VERSION 5.7 ;
  NOWIREEXTENSIONATPIN ON ;
  DIVIDERCHAR "/" ;
  BUSBITCHARS "[]" ;
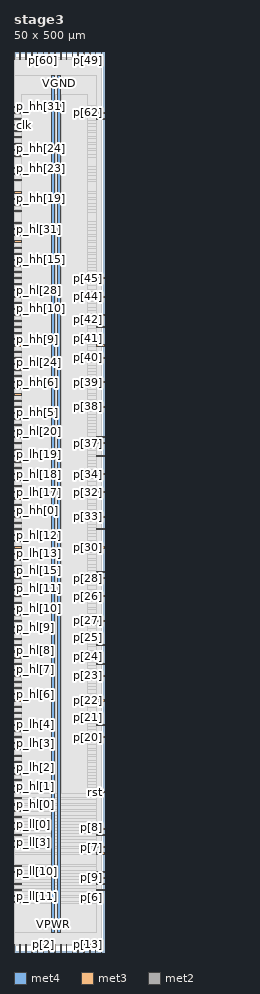
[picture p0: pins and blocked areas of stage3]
MACRO stage3
  CLASS BLOCK ;
  FOREIGN stage3 ;
  ORIGIN 0.000 0.000 ;
  SIZE 50.000 BY 500.000 ;
  PIN VGND
    DIRECTION INOUT ;
    USE GROUND ;
    PORT
      LAYER met4 ;
        RECT 24.340 10.640 25.940 487.120 ;
    END
  END VGND
  PIN VPWR
    DIRECTION INOUT ;
    USE POWER ;
    PORT
      LAYER met4 ;
        RECT 21.040 10.640 22.640 487.120 ;
    END
  END VPWR
  PIN clk
    DIRECTION INPUT ;
    USE SIGNAL ;
    ANTENNAGATEAREA 1.286700 ;
    ANTENNADIFFAREA 0.434700 ;
    PORT
      LAYER met3 ;
        RECT 0.000 459.040 4.000 459.640 ;
    END
  END clk
  PIN p[0]
    DIRECTION OUTPUT ;
    USE SIGNAL ;
    ANTENNADIFFAREA 0.445500 ;
    PORT
      LAYER met2 ;
        RECT 3.310 0.000 3.590 4.000 ;
    END
  END p[0]
  PIN p[10]
    DIRECTION OUTPUT ;
    USE SIGNAL ;
    ANTENNADIFFAREA 0.445500 ;
    PORT
      LAYER met2 ;
        RECT 0.090 0.000 0.370 4.000 ;
    END
  END p[10]
  PIN p[11]
    DIRECTION OUTPUT ;
    USE SIGNAL ;
    ANTENNADIFFAREA 0.445500 ;
    PORT
      LAYER met2 ;
        RECT 29.070 0.000 29.350 4.000 ;
    END
  END p[11]
  PIN p[12]
    DIRECTION OUTPUT ;
    USE SIGNAL ;
    ANTENNADIFFAREA 0.445500 ;
    PORT
      LAYER met2 ;
        RECT 9.750 0.000 10.030 4.000 ;
    END
  END p[12]
  PIN p[13]
    DIRECTION OUTPUT ;
    USE SIGNAL ;
    ANTENNADIFFAREA 0.445500 ;
    PORT
      LAYER met2 ;
        RECT 41.950 0.000 42.230 4.000 ;
    END
  END p[13]
  PIN p[14]
    DIRECTION OUTPUT ;
    USE SIGNAL ;
    ANTENNADIFFAREA 0.445500 ;
    PORT
      LAYER met2 ;
        RECT 12.970 0.000 13.250 4.000 ;
    END
  END p[14]
  PIN p[15]
    DIRECTION OUTPUT ;
    USE SIGNAL ;
    ANTENNADIFFAREA 0.445500 ;
    PORT
      LAYER met2 ;
        RECT 22.630 0.000 22.910 4.000 ;
    END
  END p[15]
  PIN p[16]
    DIRECTION OUTPUT ;
    USE SIGNAL ;
    ANTENNADIFFAREA 0.445500 ;
    PORT
      LAYER met2 ;
        RECT 32.290 0.000 32.570 4.000 ;
    END
  END p[16]
  PIN p[17]
    DIRECTION OUTPUT ;
    USE SIGNAL ;
    ANTENNADIFFAREA 0.445500 ;
    PORT
      LAYER met2 ;
        RECT 38.730 0.000 39.010 4.000 ;
    END
  END p[17]
  PIN p[18]
    DIRECTION OUTPUT ;
    USE SIGNAL ;
    ANTENNADIFFAREA 0.445500 ;
    PORT
      LAYER met2 ;
        RECT 6.530 0.000 6.810 4.000 ;
    END
  END p[18]
  PIN p[19]
    DIRECTION OUTPUT ;
    USE SIGNAL ;
    ANTENNADIFFAREA 0.445500 ;
    PORT
      LAYER met2 ;
        RECT 25.850 0.000 26.130 4.000 ;
    END
  END p[19]
  PIN p[1]
    DIRECTION OUTPUT ;
    USE SIGNAL ;
    ANTENNADIFFAREA 0.445500 ;
    PORT
      LAYER met2 ;
        RECT 35.510 0.000 35.790 4.000 ;
    END
  END p[1]
  PIN p[20]
    DIRECTION OUTPUT ;
    USE SIGNAL ;
    ANTENNADIFFAREA 0.445500 ;
    PORT
      LAYER met3 ;
        RECT 46.000 119.040 50.000 119.640 ;
    END
  END p[20]
  PIN p[21]
    DIRECTION OUTPUT ;
    USE SIGNAL ;
    ANTENNADIFFAREA 0.445500 ;
    PORT
      LAYER met3 ;
        RECT 46.000 125.840 50.000 126.440 ;
    END
  END p[21]
  PIN p[22]
    DIRECTION OUTPUT ;
    USE SIGNAL ;
    ANTENNADIFFAREA 0.445500 ;
    PORT
      LAYER met3 ;
        RECT 46.000 139.440 50.000 140.040 ;
    END
  END p[22]
  PIN p[23]
    DIRECTION OUTPUT ;
    USE SIGNAL ;
    ANTENNADIFFAREA 0.445500 ;
    PORT
      LAYER met3 ;
        RECT 46.000 153.040 50.000 153.640 ;
    END
  END p[23]
  PIN p[24]
    DIRECTION OUTPUT ;
    USE SIGNAL ;
    ANTENNADIFFAREA 0.445500 ;
    PORT
      LAYER met3 ;
        RECT 46.000 159.840 50.000 160.440 ;
    END
  END p[24]
  PIN p[25]
    DIRECTION OUTPUT ;
    USE SIGNAL ;
    ANTENNADIFFAREA 0.445500 ;
    PORT
      LAYER met3 ;
        RECT 46.000 170.040 50.000 170.640 ;
    END
  END p[25]
  PIN p[26]
    DIRECTION OUTPUT ;
    USE SIGNAL ;
    ANTENNADIFFAREA 0.445500 ;
    PORT
      LAYER met3 ;
        RECT 46.000 197.240 50.000 197.840 ;
    END
  END p[26]
  PIN p[27]
    DIRECTION OUTPUT ;
    USE SIGNAL ;
    ANTENNADIFFAREA 0.445500 ;
    PORT
      LAYER met3 ;
        RECT 46.000 183.640 50.000 184.240 ;
    END
  END p[27]
  PIN p[28]
    DIRECTION OUTPUT ;
    USE SIGNAL ;
    ANTENNADIFFAREA 0.445500 ;
    PORT
      LAYER met3 ;
        RECT 46.000 207.440 50.000 208.040 ;
    END
  END p[28]
  PIN p[29]
    DIRECTION OUTPUT ;
    USE SIGNAL ;
    ANTENNADIFFAREA 0.445500 ;
    PORT
      LAYER met3 ;
        RECT 46.000 210.840 50.000 211.440 ;
    END
  END p[29]
  PIN p[2]
    DIRECTION OUTPUT ;
    USE SIGNAL ;
    ANTENNADIFFAREA 0.445500 ;
    PORT
      LAYER met2 ;
        RECT 16.190 0.000 16.470 4.000 ;
    END
  END p[2]
  PIN p[30]
    DIRECTION OUTPUT ;
    USE SIGNAL ;
    ANTENNADIFFAREA 0.445500 ;
    PORT
      LAYER met3 ;
        RECT 46.000 224.440 50.000 225.040 ;
    END
  END p[30]
  PIN p[31]
    DIRECTION OUTPUT ;
    USE SIGNAL ;
    ANTENNADIFFAREA 0.445500 ;
    PORT
      LAYER met3 ;
        RECT 46.000 234.640 50.000 235.240 ;
    END
  END p[31]
  PIN p[32]
    DIRECTION OUTPUT ;
    USE SIGNAL ;
    ANTENNADIFFAREA 0.445500 ;
    PORT
      LAYER met3 ;
        RECT 46.000 255.040 50.000 255.640 ;
    END
  END p[32]
  PIN p[33]
    DIRECTION OUTPUT ;
    USE SIGNAL ;
    ANTENNADIFFAREA 0.445500 ;
    PORT
      LAYER met3 ;
        RECT 46.000 241.440 50.000 242.040 ;
    END
  END p[33]
  PIN p[34]
    DIRECTION OUTPUT ;
    USE SIGNAL ;
    ANTENNADIFFAREA 0.445500 ;
    PORT
      LAYER met3 ;
        RECT 46.000 265.240 50.000 265.840 ;
    END
  END p[34]
  PIN p[35]
    DIRECTION OUTPUT ;
    USE SIGNAL ;
    ANTENNADIFFAREA 0.445500 ;
    PORT
      LAYER met3 ;
        RECT 46.000 275.440 50.000 276.040 ;
    END
  END p[35]
  PIN p[36]
    DIRECTION OUTPUT ;
    USE SIGNAL ;
    ANTENNADIFFAREA 0.445500 ;
    PORT
      LAYER met3 ;
        RECT 46.000 285.640 50.000 286.240 ;
    END
  END p[36]
  PIN p[37]
    DIRECTION OUTPUT ;
    USE SIGNAL ;
    ANTENNADIFFAREA 0.445500 ;
    PORT
      LAYER met3 ;
        RECT 46.000 282.240 50.000 282.840 ;
    END
  END p[37]
  PIN p[38]
    DIRECTION OUTPUT ;
    USE SIGNAL ;
    ANTENNADIFFAREA 0.445500 ;
    PORT
      LAYER met3 ;
        RECT 46.000 302.640 50.000 303.240 ;
    END
  END p[38]
  PIN p[39]
    DIRECTION OUTPUT ;
    USE SIGNAL ;
    ANTENNADIFFAREA 0.445500 ;
    PORT
      LAYER met3 ;
        RECT 46.000 316.240 50.000 316.840 ;
    END
  END p[39]
  PIN p[3]
    DIRECTION OUTPUT ;
    USE SIGNAL ;
    ANTENNADIFFAREA 0.445500 ;
    PORT
      LAYER met2 ;
        RECT 19.410 0.000 19.690 4.000 ;
    END
  END p[3]
  PIN p[40]
    DIRECTION OUTPUT ;
    USE SIGNAL ;
    ANTENNADIFFAREA 0.445500 ;
    PORT
      LAYER met3 ;
        RECT 46.000 329.840 50.000 330.440 ;
    END
  END p[40]
  PIN p[41]
    DIRECTION OUTPUT ;
    USE SIGNAL ;
    ANTENNADIFFAREA 0.445500 ;
    PORT
      LAYER met3 ;
        RECT 46.000 336.640 50.000 337.240 ;
    END
  END p[41]
  PIN p[42]
    DIRECTION OUTPUT ;
    USE SIGNAL ;
    ANTENNADIFFAREA 0.445500 ;
    PORT
      LAYER met3 ;
        RECT 46.000 346.840 50.000 347.440 ;
    END
  END p[42]
  PIN p[43]
    DIRECTION OUTPUT ;
    USE SIGNAL ;
    ANTENNADIFFAREA 0.445500 ;
    PORT
      LAYER met3 ;
        RECT 46.000 353.640 50.000 354.240 ;
    END
  END p[43]
  PIN p[44]
    DIRECTION OUTPUT ;
    USE SIGNAL ;
    ANTENNADIFFAREA 0.445500 ;
    PORT
      LAYER met3 ;
        RECT 46.000 363.840 50.000 364.440 ;
    END
  END p[44]
  PIN p[45]
    DIRECTION OUTPUT ;
    USE SIGNAL ;
    ANTENNADIFFAREA 0.445500 ;
    PORT
      LAYER met3 ;
        RECT 46.000 374.040 50.000 374.640 ;
    END
  END p[45]
  PIN p[46]
    DIRECTION OUTPUT ;
    USE SIGNAL ;
    ANTENNADIFFAREA 0.445500 ;
    PORT
      LAYER met2 ;
        RECT 38.730 496.000 39.010 500.000 ;
    END
  END p[46]
  PIN p[47]
    DIRECTION OUTPUT ;
    USE SIGNAL ;
    ANTENNADIFFAREA 0.445500 ;
    PORT
      LAYER met2 ;
        RECT 3.310 496.000 3.590 500.000 ;
    END
  END p[47]
  PIN p[48]
    DIRECTION OUTPUT ;
    USE SIGNAL ;
    ANTENNADIFFAREA 0.445500 ;
    PORT
      LAYER met2 ;
        RECT 0.090 496.000 0.370 500.000 ;
    END
  END p[48]
  PIN p[49]
    DIRECTION OUTPUT ;
    USE SIGNAL ;
    ANTENNADIFFAREA 0.445500 ;
    PORT
      LAYER met2 ;
        RECT 41.950 496.000 42.230 500.000 ;
    END
  END p[49]
  PIN p[4]
    DIRECTION OUTPUT ;
    USE SIGNAL ;
    ANTENNADIFFAREA 0.445500 ;
    PORT
      LAYER met2 ;
        RECT 45.170 0.000 45.450 4.000 ;
    END
  END p[4]
  PIN p[50]
    DIRECTION OUTPUT ;
    USE SIGNAL ;
    ANTENNADIFFAREA 0.445500 ;
    PORT
      LAYER met2 ;
        RECT 6.530 496.000 6.810 500.000 ;
    END
  END p[50]
  PIN p[51]
    DIRECTION OUTPUT ;
    USE SIGNAL ;
    ANTENNADIFFAREA 0.445500 ;
    PORT
      LAYER met2 ;
        RECT 35.510 496.000 35.790 500.000 ;
    END
  END p[51]
  PIN p[52]
    DIRECTION OUTPUT ;
    USE SIGNAL ;
    ANTENNADIFFAREA 0.445500 ;
    PORT
      LAYER met2 ;
        RECT 12.970 496.000 13.250 500.000 ;
    END
  END p[52]
  PIN p[53]
    DIRECTION OUTPUT ;
    USE SIGNAL ;
    ANTENNADIFFAREA 0.445500 ;
    PORT
      LAYER met2 ;
        RECT 9.750 496.000 10.030 500.000 ;
    END
  END p[53]
  PIN p[54]
    DIRECTION OUTPUT ;
    USE SIGNAL ;
    ANTENNADIFFAREA 0.445500 ;
    PORT
      LAYER met2 ;
        RECT 25.850 496.000 26.130 500.000 ;
    END
  END p[54]
  PIN p[55]
    DIRECTION OUTPUT ;
    USE SIGNAL ;
    ANTENNADIFFAREA 0.445500 ;
    PORT
      LAYER met2 ;
        RECT 22.630 496.000 22.910 500.000 ;
    END
  END p[55]
  PIN p[56]
    DIRECTION OUTPUT ;
    USE SIGNAL ;
    ANTENNADIFFAREA 0.445500 ;
    PORT
      LAYER met2 ;
        RECT 48.390 496.000 48.670 500.000 ;
    END
  END p[56]
  PIN p[57]
    DIRECTION OUTPUT ;
    USE SIGNAL ;
    ANTENNADIFFAREA 0.445500 ;
    PORT
      LAYER met2 ;
        RECT 29.070 496.000 29.350 500.000 ;
    END
  END p[57]
  PIN p[58]
    DIRECTION OUTPUT ;
    USE SIGNAL ;
    ANTENNADIFFAREA 0.445500 ;
    PORT
      LAYER met2 ;
        RECT 45.170 496.000 45.450 500.000 ;
    END
  END p[58]
  PIN p[59]
    DIRECTION OUTPUT ;
    USE SIGNAL ;
    ANTENNADIFFAREA 0.445500 ;
    PORT
      LAYER met2 ;
        RECT 19.410 496.000 19.690 500.000 ;
    END
  END p[59]
  PIN p[5]
    DIRECTION OUTPUT ;
    USE SIGNAL ;
    ANTENNADIFFAREA 0.445500 ;
    PORT
      LAYER met2 ;
        RECT 48.390 0.000 48.670 4.000 ;
    END
  END p[5]
  PIN p[60]
    DIRECTION OUTPUT ;
    USE SIGNAL ;
    ANTENNADIFFAREA 0.445500 ;
    PORT
      LAYER met2 ;
        RECT 16.190 496.000 16.470 500.000 ;
    END
  END p[60]
  PIN p[61]
    DIRECTION OUTPUT ;
    USE SIGNAL ;
    ANTENNADIFFAREA 0.445500 ;
    PORT
      LAYER met2 ;
        RECT 32.290 496.000 32.570 500.000 ;
    END
  END p[61]
  PIN p[62]
    DIRECTION OUTPUT ;
    USE SIGNAL ;
    ANTENNADIFFAREA 0.445500 ;
    PORT
      LAYER met3 ;
        RECT 46.000 465.840 50.000 466.440 ;
    END
  END p[62]
  PIN p[63]
    DIRECTION OUTPUT ;
    USE SIGNAL ;
    ANTENNADIFFAREA 0.445500 ;
    PORT
      LAYER met3 ;
        RECT 46.000 462.440 50.000 463.040 ;
    END
  END p[63]
  PIN p[6]
    DIRECTION OUTPUT ;
    USE SIGNAL ;
    ANTENNADIFFAREA 0.445500 ;
    PORT
      LAYER met3 ;
        RECT 46.000 34.040 50.000 34.640 ;
    END
  END p[6]
  PIN p[7]
    DIRECTION OUTPUT ;
    USE SIGNAL ;
    ANTENNADIFFAREA 0.445500 ;
    PORT
      LAYER met3 ;
        RECT 46.000 57.840 50.000 58.440 ;
    END
  END p[7]
  PIN p[8]
    DIRECTION OUTPUT ;
    USE SIGNAL ;
    ANTENNADIFFAREA 0.445500 ;
    PORT
      LAYER met3 ;
        RECT 46.000 64.640 50.000 65.240 ;
    END
  END p[8]
  PIN p[9]
    DIRECTION OUTPUT ;
    USE SIGNAL ;
    ANTENNADIFFAREA 0.445500 ;
    PORT
      LAYER met3 ;
        RECT 46.000 40.840 50.000 41.440 ;
    END
  END p[9]
  PIN p_hh[0]
    DIRECTION INPUT ;
    USE SIGNAL ;
    ANTENNAGATEAREA 0.631200 ;
    ANTENNADIFFAREA 0.434700 ;
    PORT
      LAYER met3 ;
        RECT 0.000 244.840 4.000 245.440 ;
    END
  END p_hh[0]
  PIN p_hh[10]
    DIRECTION INPUT ;
    USE SIGNAL ;
    ANTENNAGATEAREA 0.631200 ;
    ANTENNADIFFAREA 0.434700 ;
    PORT
      LAYER met3 ;
        RECT 0.000 357.040 4.000 357.640 ;
    END
  END p_hh[10]
  PIN p_hh[11]
    DIRECTION INPUT ;
    USE SIGNAL ;
    ANTENNAGATEAREA 0.631200 ;
    ANTENNADIFFAREA 0.434700 ;
    PORT
      LAYER met3 ;
        RECT 0.000 360.440 4.000 361.040 ;
    END
  END p_hh[11]
  PIN p_hh[12]
    DIRECTION INPUT ;
    USE SIGNAL ;
    ANTENNAGATEAREA 0.631200 ;
    ANTENNADIFFAREA 0.434700 ;
    PORT
      LAYER met3 ;
        RECT 0.000 380.840 4.000 381.440 ;
    END
  END p_hh[12]
  PIN p_hh[13]
    DIRECTION INPUT ;
    USE SIGNAL ;
    ANTENNAGATEAREA 0.631200 ;
    ANTENNADIFFAREA 0.434700 ;
    PORT
      LAYER met3 ;
        RECT 0.000 363.840 4.000 364.440 ;
    END
  END p_hh[13]
  PIN p_hh[14]
    DIRECTION INPUT ;
    USE SIGNAL ;
    ANTENNAGATEAREA 0.631200 ;
    ANTENNADIFFAREA 0.434700 ;
    PORT
      LAYER met3 ;
        RECT 0.000 394.440 4.000 395.040 ;
    END
  END p_hh[14]
  PIN p_hh[15]
    DIRECTION INPUT ;
    USE SIGNAL ;
    ANTENNAGATEAREA 0.631200 ;
    ANTENNADIFFAREA 0.434700 ;
    PORT
      LAYER met3 ;
        RECT 0.000 384.240 4.000 384.840 ;
    END
  END p_hh[15]
  PIN p_hh[16]
    DIRECTION INPUT ;
    USE SIGNAL ;
    ANTENNAGATEAREA 0.631200 ;
    ANTENNADIFFAREA 0.434700 ;
    PORT
      LAYER met3 ;
        RECT 0.000 404.640 4.000 405.240 ;
    END
  END p_hh[16]
  PIN p_hh[17]
    DIRECTION INPUT ;
    USE SIGNAL ;
    ANTENNAGATEAREA 0.631200 ;
    ANTENNADIFFAREA 0.434700 ;
    PORT
      LAYER met3 ;
        RECT 0.000 411.440 4.000 412.040 ;
    END
  END p_hh[17]
  PIN p_hh[18]
    DIRECTION INPUT ;
    USE SIGNAL ;
    ANTENNAGATEAREA 0.631200 ;
    ANTENNADIFFAREA 0.434700 ;
    PORT
      LAYER met3 ;
        RECT 0.000 414.840 4.000 415.440 ;
    END
  END p_hh[18]
  PIN p_hh[19]
    DIRECTION INPUT ;
    USE SIGNAL ;
    ANTENNAGATEAREA 0.631200 ;
    ANTENNADIFFAREA 0.434700 ;
    PORT
      LAYER met3 ;
        RECT 0.000 418.240 4.000 418.840 ;
    END
  END p_hh[19]
  PIN p_hh[1]
    DIRECTION INPUT ;
    USE SIGNAL ;
    ANTENNAGATEAREA 0.631200 ;
    ANTENNADIFFAREA 0.434700 ;
    PORT
      LAYER met3 ;
        RECT 0.000 241.440 4.000 242.040 ;
    END
  END p_hh[1]
  PIN p_hh[20]
    DIRECTION INPUT ;
    USE SIGNAL ;
    ANTENNAGATEAREA 0.631200 ;
    ANTENNADIFFAREA 0.434700 ;
    PORT
      LAYER met3 ;
        RECT 0.000 431.840 4.000 432.440 ;
    END
  END p_hh[20]
  PIN p_hh[21]
    DIRECTION INPUT ;
    USE SIGNAL ;
    ANTENNAGATEAREA 0.631200 ;
    ANTENNADIFFAREA 0.434700 ;
    PORT
      LAYER met3 ;
        RECT 0.000 428.440 4.000 429.040 ;
    END
  END p_hh[21]
  PIN p_hh[22]
    DIRECTION INPUT ;
    USE SIGNAL ;
    ANTENNAGATEAREA 0.631200 ;
    ANTENNADIFFAREA 0.434700 ;
    PORT
      LAYER met3 ;
        RECT 0.000 421.640 4.000 422.240 ;
    END
  END p_hh[22]
  PIN p_hh[23]
    DIRECTION INPUT ;
    USE SIGNAL ;
    ANTENNAGATEAREA 0.631200 ;
    ANTENNADIFFAREA 0.434700 ;
    PORT
      LAYER met3 ;
        RECT 0.000 435.240 4.000 435.840 ;
    END
  END p_hh[23]
  PIN p_hh[24]
    DIRECTION INPUT ;
    USE SIGNAL ;
    ANTENNAGATEAREA 0.631200 ;
    ANTENNADIFFAREA 0.434700 ;
    PORT
      LAYER met3 ;
        RECT 0.000 442.040 4.000 442.640 ;
    END
  END p_hh[24]
  PIN p_hh[25]
    DIRECTION INPUT ;
    USE SIGNAL ;
    ANTENNAGATEAREA 0.631200 ;
    ANTENNADIFFAREA 0.434700 ;
    PORT
      LAYER met3 ;
        RECT 0.000 445.440 4.000 446.040 ;
    END
  END p_hh[25]
  PIN p_hh[26]
    DIRECTION INPUT ;
    USE SIGNAL ;
    ANTENNAGATEAREA 0.631200 ;
    ANTENNADIFFAREA 0.434700 ;
    PORT
      LAYER met3 ;
        RECT 0.000 448.840 4.000 449.440 ;
    END
  END p_hh[26]
  PIN p_hh[27]
    DIRECTION INPUT ;
    USE SIGNAL ;
    ANTENNAGATEAREA 0.631200 ;
    ANTENNADIFFAREA 0.434700 ;
    PORT
      LAYER met3 ;
        RECT 0.000 452.240 4.000 452.840 ;
    END
  END p_hh[27]
  PIN p_hh[28]
    DIRECTION INPUT ;
    USE SIGNAL ;
    ANTENNAGATEAREA 0.631200 ;
    ANTENNADIFFAREA 0.434700 ;
    PORT
      LAYER met3 ;
        RECT 0.000 455.640 4.000 456.240 ;
    END
  END p_hh[28]
  PIN p_hh[29]
    DIRECTION INPUT ;
    USE SIGNAL ;
    ANTENNAGATEAREA 0.631200 ;
    ANTENNADIFFAREA 0.434700 ;
    PORT
      LAYER met3 ;
        RECT 0.000 462.440 4.000 463.040 ;
    END
  END p_hh[29]
  PIN p_hh[2]
    DIRECTION INPUT ;
    USE SIGNAL ;
    ANTENNAGATEAREA 0.631200 ;
    ANTENNADIFFAREA 0.434700 ;
    PORT
      LAYER met3 ;
        RECT 0.000 261.840 4.000 262.440 ;
    END
  END p_hh[2]
  PIN p_hh[30]
    DIRECTION INPUT ;
    USE SIGNAL ;
    ANTENNAGATEAREA 0.631200 ;
    ANTENNADIFFAREA 0.434700 ;
    PORT
      LAYER met3 ;
        RECT 0.000 465.840 4.000 466.440 ;
    END
  END p_hh[30]
  PIN p_hh[31]
    DIRECTION INPUT ;
    USE SIGNAL ;
    ANTENNAGATEAREA 0.631200 ;
    ANTENNADIFFAREA 0.434700 ;
    PORT
      LAYER met3 ;
        RECT 0.000 469.240 4.000 469.840 ;
    END
  END p_hh[31]
  PIN p_hh[3]
    DIRECTION INPUT ;
    USE SIGNAL ;
    ANTENNAGATEAREA 0.631200 ;
    ANTENNADIFFAREA 0.434700 ;
    PORT
      LAYER met3 ;
        RECT 0.000 278.840 4.000 279.440 ;
    END
  END p_hh[3]
  PIN p_hh[4]
    DIRECTION INPUT ;
    USE SIGNAL ;
    ANTENNAGATEAREA 0.631200 ;
    ANTENNADIFFAREA 0.434700 ;
    PORT
      LAYER met3 ;
        RECT 0.000 285.640 4.000 286.240 ;
    END
  END p_hh[4]
  PIN p_hh[5]
    DIRECTION INPUT ;
    USE SIGNAL ;
    ANTENNAGATEAREA 0.631200 ;
    ANTENNADIFFAREA 0.434700 ;
    PORT
      LAYER met3 ;
        RECT 0.000 299.240 4.000 299.840 ;
    END
  END p_hh[5]
  PIN p_hh[6]
    DIRECTION INPUT ;
    USE SIGNAL ;
    ANTENNAGATEAREA 0.631200 ;
    ANTENNADIFFAREA 0.434700 ;
    PORT
      LAYER met3 ;
        RECT 0.000 316.240 4.000 316.840 ;
    END
  END p_hh[6]
  PIN p_hh[7]
    DIRECTION INPUT ;
    USE SIGNAL ;
    ANTENNAGATEAREA 0.631200 ;
    ANTENNADIFFAREA 0.434700 ;
    PORT
      LAYER met3 ;
        RECT 0.000 319.640 4.000 320.240 ;
    END
  END p_hh[7]
  PIN p_hh[8]
    DIRECTION INPUT ;
    USE SIGNAL ;
    ANTENNAGATEAREA 0.631200 ;
    ANTENNADIFFAREA 0.434700 ;
    PORT
      LAYER met3 ;
        RECT 0.000 329.840 4.000 330.440 ;
    END
  END p_hh[8]
  PIN p_hh[9]
    DIRECTION INPUT ;
    USE SIGNAL ;
    ANTENNAGATEAREA 0.631200 ;
    ANTENNADIFFAREA 0.434700 ;
    PORT
      LAYER met3 ;
        RECT 0.000 340.040 4.000 340.640 ;
    END
  END p_hh[9]
  PIN p_hl[0]
    DIRECTION INPUT ;
    USE SIGNAL ;
    ANTENNAGATEAREA 0.647700 ;
    ANTENNADIFFAREA 0.434700 ;
    PORT
      LAYER met3 ;
        RECT 0.000 81.640 4.000 82.240 ;
    END
  END p_hl[0]
  PIN p_hl[10]
    DIRECTION INPUT ;
    USE SIGNAL ;
    ANTENNAGATEAREA 0.631200 ;
    ANTENNADIFFAREA 0.434700 ;
    PORT
      LAYER met3 ;
        RECT 0.000 190.440 4.000 191.040 ;
    END
  END p_hl[10]
  PIN p_hl[11]
    DIRECTION INPUT ;
    USE SIGNAL ;
    ANTENNAGATEAREA 0.631200 ;
    ANTENNADIFFAREA 0.434700 ;
    PORT
      LAYER met3 ;
        RECT 0.000 197.240 4.000 197.840 ;
    END
  END p_hl[11]
  PIN p_hl[12]
    DIRECTION INPUT ;
    USE SIGNAL ;
    ANTENNAGATEAREA 0.631200 ;
    ANTENNADIFFAREA 0.434700 ;
    PORT
      LAYER met3 ;
        RECT 0.000 231.240 4.000 231.840 ;
    END
  END p_hl[12]
  PIN p_hl[13]
    DIRECTION INPUT ;
    USE SIGNAL ;
    ANTENNAGATEAREA 0.631200 ;
    ANTENNADIFFAREA 0.434700 ;
    PORT
      LAYER met3 ;
        RECT 0.000 217.640 4.000 218.240 ;
    END
  END p_hl[13]
  PIN p_hl[14]
    DIRECTION INPUT ;
    USE SIGNAL ;
    ANTENNAGATEAREA 0.631200 ;
    ANTENNADIFFAREA 0.434700 ;
    PORT
      LAYER met3 ;
        RECT 0.000 227.840 4.000 228.440 ;
    END
  END p_hl[14]
  PIN p_hl[15]
    DIRECTION INPUT ;
    USE SIGNAL ;
    ANTENNAGATEAREA 0.631200 ;
    ANTENNADIFFAREA 0.434700 ;
    PORT
      LAYER met3 ;
        RECT 0.000 207.440 4.000 208.040 ;
    END
  END p_hl[15]
  PIN p_hl[16]
    DIRECTION INPUT ;
    USE SIGNAL ;
    ANTENNAGATEAREA 0.631200 ;
    ANTENNADIFFAREA 0.434700 ;
    PORT
      LAYER met3 ;
        RECT 0.000 258.440 4.000 259.040 ;
    END
  END p_hl[16]
  PIN p_hl[17]
    DIRECTION INPUT ;
    USE SIGNAL ;
    ANTENNAGATEAREA 0.631200 ;
    ANTENNADIFFAREA 0.434700 ;
    PORT
      LAYER met3 ;
        RECT 0.000 251.640 4.000 252.240 ;
    END
  END p_hl[17]
  PIN p_hl[18]
    DIRECTION INPUT ;
    USE SIGNAL ;
    ANTENNAGATEAREA 0.631200 ;
    ANTENNADIFFAREA 0.434700 ;
    PORT
      LAYER met3 ;
        RECT 0.000 265.240 4.000 265.840 ;
    END
  END p_hl[18]
  PIN p_hl[19]
    DIRECTION INPUT ;
    USE SIGNAL ;
    ANTENNAGATEAREA 0.631200 ;
    ANTENNADIFFAREA 0.434700 ;
    PORT
      LAYER met3 ;
        RECT 0.000 268.640 4.000 269.240 ;
    END
  END p_hl[19]
  PIN p_hl[1]
    DIRECTION INPUT ;
    USE SIGNAL ;
    ANTENNAGATEAREA 0.647700 ;
    ANTENNADIFFAREA 0.434700 ;
    PORT
      LAYER met3 ;
        RECT 0.000 91.840 4.000 92.440 ;
    END
  END p_hl[1]
  PIN p_hl[20]
    DIRECTION INPUT ;
    USE SIGNAL ;
    ANTENNAGATEAREA 0.631200 ;
    ANTENNADIFFAREA 0.434700 ;
    PORT
      LAYER met3 ;
        RECT 0.000 289.040 4.000 289.640 ;
    END
  END p_hl[20]
  PIN p_hl[21]
    DIRECTION INPUT ;
    USE SIGNAL ;
    ANTENNAGATEAREA 0.631200 ;
    ANTENNADIFFAREA 0.434700 ;
    PORT
      LAYER met3 ;
        RECT 0.000 295.840 4.000 296.440 ;
    END
  END p_hl[21]
  PIN p_hl[22]
    DIRECTION INPUT ;
    USE SIGNAL ;
    ANTENNAGATEAREA 0.631200 ;
    ANTENNADIFFAREA 0.434700 ;
    PORT
      LAYER met3 ;
        RECT 0.000 312.840 4.000 313.440 ;
    END
  END p_hl[22]
  PIN p_hl[23]
    DIRECTION INPUT ;
    USE SIGNAL ;
    ANTENNAGATEAREA 0.631200 ;
    ANTENNADIFFAREA 0.434700 ;
    PORT
      LAYER met3 ;
        RECT 0.000 306.040 4.000 306.640 ;
    END
  END p_hl[23]
  PIN p_hl[24]
    DIRECTION INPUT ;
    USE SIGNAL ;
    ANTENNAGATEAREA 0.647700 ;
    ANTENNADIFFAREA 0.434700 ;
    PORT
      LAYER met3 ;
        RECT 0.000 323.040 4.000 323.640 ;
    END
  END p_hl[24]
  PIN p_hl[25]
    DIRECTION INPUT ;
    USE SIGNAL ;
    ANTENNAGATEAREA 0.631200 ;
    ANTENNADIFFAREA 0.434700 ;
    PORT
      LAYER met3 ;
        RECT 0.000 336.640 4.000 337.240 ;
    END
  END p_hl[25]
  PIN p_hl[26]
    DIRECTION INPUT ;
    USE SIGNAL ;
    ANTENNAGATEAREA 0.631200 ;
    ANTENNADIFFAREA 0.434700 ;
    PORT
      LAYER met3 ;
        RECT 0.000 343.440 4.000 344.040 ;
    END
  END p_hl[26]
  PIN p_hl[27]
    DIRECTION INPUT ;
    USE SIGNAL ;
    ANTENNAGATEAREA 0.631200 ;
    ANTENNADIFFAREA 0.434700 ;
    PORT
      LAYER met3 ;
        RECT 0.000 353.640 4.000 354.240 ;
    END
  END p_hl[27]
  PIN p_hl[28]
    DIRECTION INPUT ;
    USE SIGNAL ;
    ANTENNAGATEAREA 0.631200 ;
    ANTENNADIFFAREA 0.434700 ;
    PORT
      LAYER met3 ;
        RECT 0.000 367.240 4.000 367.840 ;
    END
  END p_hl[28]
  PIN p_hl[29]
    DIRECTION INPUT ;
    USE SIGNAL ;
    ANTENNAGATEAREA 0.631200 ;
    ANTENNADIFFAREA 0.434700 ;
    PORT
      LAYER met3 ;
        RECT 0.000 377.440 4.000 378.040 ;
    END
  END p_hl[29]
  PIN p_hl[2]
    DIRECTION INPUT ;
    USE SIGNAL ;
    ANTENNAGATEAREA 0.631200 ;
    ANTENNADIFFAREA 0.434700 ;
    PORT
      LAYER met3 ;
        RECT 0.000 105.440 4.000 106.040 ;
    END
  END p_hl[2]
  PIN p_hl[30]
    DIRECTION INPUT ;
    USE SIGNAL ;
    ANTENNAGATEAREA 0.631200 ;
    ANTENNADIFFAREA 0.434700 ;
    PORT
      LAYER met3 ;
        RECT 0.000 387.640 4.000 388.240 ;
    END
  END p_hl[30]
  PIN p_hl[31]
    DIRECTION INPUT ;
    USE SIGNAL ;
    ANTENNAGATEAREA 0.631200 ;
    ANTENNADIFFAREA 0.434700 ;
    PORT
      LAYER met3 ;
        RECT 0.000 401.240 4.000 401.840 ;
    END
  END p_hl[31]
  PIN p_hl[3]
    DIRECTION INPUT ;
    USE SIGNAL ;
    ANTENNAGATEAREA 0.631200 ;
    ANTENNADIFFAREA 0.434700 ;
    PORT
      LAYER met3 ;
        RECT 0.000 112.240 4.000 112.840 ;
    END
  END p_hl[3]
  PIN p_hl[4]
    DIRECTION INPUT ;
    USE SIGNAL ;
    ANTENNAGATEAREA 0.631200 ;
    ANTENNADIFFAREA 0.434700 ;
    PORT
      LAYER met3 ;
        RECT 0.000 122.440 4.000 123.040 ;
    END
  END p_hl[4]
  PIN p_hl[5]
    DIRECTION INPUT ;
    USE SIGNAL ;
    ANTENNAGATEAREA 0.631200 ;
    ANTENNADIFFAREA 0.434700 ;
    PORT
      LAYER met3 ;
        RECT 0.000 132.640 4.000 133.240 ;
    END
  END p_hl[5]
  PIN p_hl[6]
    DIRECTION INPUT ;
    USE SIGNAL ;
    ANTENNAGATEAREA 0.647700 ;
    ANTENNADIFFAREA 0.434700 ;
    PORT
      LAYER met3 ;
        RECT 0.000 142.840 4.000 143.440 ;
    END
  END p_hl[6]
  PIN p_hl[7]
    DIRECTION INPUT ;
    USE SIGNAL ;
    ANTENNAGATEAREA 0.631200 ;
    ANTENNADIFFAREA 0.434700 ;
    PORT
      LAYER met3 ;
        RECT 0.000 156.440 4.000 157.040 ;
    END
  END p_hl[7]
  PIN p_hl[8]
    DIRECTION INPUT ;
    USE SIGNAL ;
    ANTENNAGATEAREA 0.631200 ;
    ANTENNADIFFAREA 0.434700 ;
    PORT
      LAYER met3 ;
        RECT 0.000 163.240 4.000 163.840 ;
    END
  END p_hl[8]
  PIN p_hl[9]
    DIRECTION INPUT ;
    USE SIGNAL ;
    ANTENNAGATEAREA 0.631200 ;
    ANTENNADIFFAREA 0.434700 ;
    PORT
      LAYER met3 ;
        RECT 0.000 180.240 4.000 180.840 ;
    END
  END p_hl[9]
  PIN p_lh[0]
    DIRECTION INPUT ;
    USE SIGNAL ;
    ANTENNAGATEAREA 0.647700 ;
    ANTENNADIFFAREA 0.434700 ;
    PORT
      LAYER met3 ;
        RECT 0.000 88.440 4.000 89.040 ;
    END
  END p_lh[0]
  PIN p_lh[10]
    DIRECTION INPUT ;
    USE SIGNAL ;
    ANTENNAGATEAREA 0.631200 ;
    ANTENNADIFFAREA 0.434700 ;
    PORT
      LAYER met3 ;
        RECT 0.000 183.640 4.000 184.240 ;
    END
  END p_lh[10]
  PIN p_lh[11]
    DIRECTION INPUT ;
    USE SIGNAL ;
    ANTENNAGATEAREA 0.631200 ;
    ANTENNADIFFAREA 0.434700 ;
    PORT
      LAYER met3 ;
        RECT 0.000 193.840 4.000 194.440 ;
    END
  END p_lh[11]
  PIN p_lh[12]
    DIRECTION INPUT ;
    USE SIGNAL ;
    ANTENNAGATEAREA 0.631200 ;
    ANTENNADIFFAREA 0.434700 ;
    PORT
      LAYER met3 ;
        RECT 0.000 214.240 4.000 214.840 ;
    END
  END p_lh[12]
  PIN p_lh[13]
    DIRECTION INPUT ;
    USE SIGNAL ;
    ANTENNAGATEAREA 0.631200 ;
    ANTENNADIFFAREA 0.434700 ;
    PORT
      LAYER met3 ;
        RECT 0.000 221.040 4.000 221.640 ;
    END
  END p_lh[13]
  PIN p_lh[14]
    DIRECTION INPUT ;
    USE SIGNAL ;
    ANTENNAGATEAREA 0.631200 ;
    ANTENNADIFFAREA 0.434700 ;
    PORT
      LAYER met3 ;
        RECT 0.000 224.440 4.000 225.040 ;
    END
  END p_lh[14]
  PIN p_lh[15]
    DIRECTION INPUT ;
    USE SIGNAL ;
    ANTENNAGATEAREA 0.631200 ;
    ANTENNADIFFAREA 0.434700 ;
    PORT
      LAYER met3 ;
        RECT 0.000 210.840 4.000 211.440 ;
    END
  END p_lh[15]
  PIN p_lh[16]
    DIRECTION INPUT ;
    USE SIGNAL ;
    ANTENNAGATEAREA 0.631200 ;
    ANTENNADIFFAREA 0.434700 ;
    PORT
      LAYER met3 ;
        RECT 0.000 248.240 4.000 248.840 ;
    END
  END p_lh[16]
  PIN p_lh[17]
    DIRECTION INPUT ;
    USE SIGNAL ;
    ANTENNAGATEAREA 0.631200 ;
    ANTENNADIFFAREA 0.434700 ;
    PORT
      LAYER met3 ;
        RECT 0.000 255.040 4.000 255.640 ;
    END
  END p_lh[17]
  PIN p_lh[18]
    DIRECTION INPUT ;
    USE SIGNAL ;
    ANTENNAGATEAREA 0.631200 ;
    ANTENNADIFFAREA 0.434700 ;
    PORT
      LAYER met3 ;
        RECT 0.000 275.440 4.000 276.040 ;
    END
  END p_lh[18]
  PIN p_lh[19]
    DIRECTION INPUT ;
    USE SIGNAL ;
    ANTENNAGATEAREA 0.631200 ;
    ANTENNADIFFAREA 0.434700 ;
    PORT
      LAYER met3 ;
        RECT 0.000 272.040 4.000 272.640 ;
    END
  END p_lh[19]
  PIN p_lh[1]
    DIRECTION INPUT ;
    USE SIGNAL ;
    ANTENNAGATEAREA 0.647700 ;
    ANTENNADIFFAREA 0.434700 ;
    PORT
      LAYER met3 ;
        RECT 0.000 95.240 4.000 95.840 ;
    END
  END p_lh[1]
  PIN p_lh[20]
    DIRECTION INPUT ;
    USE SIGNAL ;
    ANTENNAGATEAREA 0.631200 ;
    ANTENNADIFFAREA 0.434700 ;
    PORT
      LAYER met3 ;
        RECT 0.000 282.240 4.000 282.840 ;
    END
  END p_lh[20]
  PIN p_lh[21]
    DIRECTION INPUT ;
    USE SIGNAL ;
    ANTENNAGATEAREA 0.631200 ;
    ANTENNADIFFAREA 0.434700 ;
    PORT
      LAYER met3 ;
        RECT 0.000 292.440 4.000 293.040 ;
    END
  END p_lh[21]
  PIN p_lh[22]
    DIRECTION INPUT ;
    USE SIGNAL ;
    ANTENNAGATEAREA 0.631200 ;
    ANTENNADIFFAREA 0.434700 ;
    PORT
      LAYER met3 ;
        RECT 0.000 309.440 4.000 310.040 ;
    END
  END p_lh[22]
  PIN p_lh[23]
    DIRECTION INPUT ;
    USE SIGNAL ;
    ANTENNAGATEAREA 0.631200 ;
    ANTENNADIFFAREA 0.434700 ;
    PORT
      LAYER met3 ;
        RECT 0.000 302.640 4.000 303.240 ;
    END
  END p_lh[23]
  PIN p_lh[24]
    DIRECTION INPUT ;
    USE SIGNAL ;
    ANTENNAGATEAREA 0.560700 ;
    ANTENNADIFFAREA 0.434700 ;
    PORT
      LAYER met3 ;
        RECT 0.000 326.440 4.000 327.040 ;
    END
  END p_lh[24]
  PIN p_lh[25]
    DIRECTION INPUT ;
    USE SIGNAL ;
    ANTENNAGATEAREA 0.631200 ;
    ANTENNADIFFAREA 0.434700 ;
    PORT
      LAYER met3 ;
        RECT 0.000 333.240 4.000 333.840 ;
    END
  END p_lh[25]
  PIN p_lh[26]
    DIRECTION INPUT ;
    USE SIGNAL ;
    ANTENNAGATEAREA 0.631200 ;
    ANTENNADIFFAREA 0.434700 ;
    PORT
      LAYER met3 ;
        RECT 0.000 346.840 4.000 347.440 ;
    END
  END p_lh[26]
  PIN p_lh[27]
    DIRECTION INPUT ;
    USE SIGNAL ;
    ANTENNAGATEAREA 0.631200 ;
    ANTENNADIFFAREA 0.434700 ;
    PORT
      LAYER met3 ;
        RECT 0.000 350.240 4.000 350.840 ;
    END
  END p_lh[27]
  PIN p_lh[28]
    DIRECTION INPUT ;
    USE SIGNAL ;
    ANTENNAGATEAREA 0.631200 ;
    ANTENNADIFFAREA 0.434700 ;
    PORT
      LAYER met3 ;
        RECT 0.000 370.640 4.000 371.240 ;
    END
  END p_lh[28]
  PIN p_lh[29]
    DIRECTION INPUT ;
    USE SIGNAL ;
    ANTENNAGATEAREA 0.631200 ;
    ANTENNADIFFAREA 0.434700 ;
    PORT
      LAYER met3 ;
        RECT 0.000 374.040 4.000 374.640 ;
    END
  END p_lh[29]
  PIN p_lh[2]
    DIRECTION INPUT ;
    USE SIGNAL ;
    ANTENNAGATEAREA 0.631200 ;
    ANTENNADIFFAREA 0.434700 ;
    PORT
      LAYER met3 ;
        RECT 0.000 102.040 4.000 102.640 ;
    END
  END p_lh[2]
  PIN p_lh[30]
    DIRECTION INPUT ;
    USE SIGNAL ;
    ANTENNAGATEAREA 0.631200 ;
    ANTENNADIFFAREA 0.434700 ;
    PORT
      LAYER met3 ;
        RECT 0.000 391.040 4.000 391.640 ;
    END
  END p_lh[30]
  PIN p_lh[31]
    DIRECTION INPUT ;
    USE SIGNAL ;
    ANTENNAGATEAREA 0.631200 ;
    ANTENNADIFFAREA 0.434700 ;
    PORT
      LAYER met3 ;
        RECT 0.000 397.840 4.000 398.440 ;
    END
  END p_lh[31]
  PIN p_lh[3]
    DIRECTION INPUT ;
    USE SIGNAL ;
    ANTENNAGATEAREA 0.631200 ;
    ANTENNADIFFAREA 0.434700 ;
    PORT
      LAYER met3 ;
        RECT 0.000 115.640 4.000 116.240 ;
    END
  END p_lh[3]
  PIN p_lh[4]
    DIRECTION INPUT ;
    USE SIGNAL ;
    ANTENNAGATEAREA 0.631200 ;
    ANTENNADIFFAREA 0.434700 ;
    PORT
      LAYER met3 ;
        RECT 0.000 125.840 4.000 126.440 ;
    END
  END p_lh[4]
  PIN p_lh[5]
    DIRECTION INPUT ;
    USE SIGNAL ;
    ANTENNAGATEAREA 0.631200 ;
    ANTENNADIFFAREA 0.434700 ;
    PORT
      LAYER met3 ;
        RECT 0.000 129.240 4.000 129.840 ;
    END
  END p_lh[5]
  PIN p_lh[6]
    DIRECTION INPUT ;
    USE SIGNAL ;
    ANTENNAGATEAREA 0.647700 ;
    ANTENNADIFFAREA 0.434700 ;
    PORT
      LAYER met3 ;
        RECT 0.000 146.240 4.000 146.840 ;
    END
  END p_lh[6]
  PIN p_lh[7]
    DIRECTION INPUT ;
    USE SIGNAL ;
    ANTENNAGATEAREA 0.631200 ;
    ANTENNADIFFAREA 0.434700 ;
    PORT
      LAYER met3 ;
        RECT 0.000 153.040 4.000 153.640 ;
    END
  END p_lh[7]
  PIN p_lh[8]
    DIRECTION INPUT ;
    USE SIGNAL ;
    ANTENNAGATEAREA 0.631200 ;
    ANTENNADIFFAREA 0.434700 ;
    PORT
      LAYER met3 ;
        RECT 0.000 170.040 4.000 170.640 ;
    END
  END p_lh[8]
  PIN p_lh[9]
    DIRECTION INPUT ;
    USE SIGNAL ;
    ANTENNAGATEAREA 0.631200 ;
    ANTENNADIFFAREA 0.434700 ;
    PORT
      LAYER met3 ;
        RECT 0.000 173.440 4.000 174.040 ;
    END
  END p_lh[9]
  PIN p_ll[0]
    DIRECTION INPUT ;
    USE SIGNAL ;
    ANTENNAGATEAREA 0.631200 ;
    ANTENNADIFFAREA 0.434700 ;
    PORT
      LAYER met3 ;
        RECT 0.000 74.840 4.000 75.440 ;
    END
  END p_ll[0]
  PIN p_ll[10]
    DIRECTION INPUT ;
    USE SIGNAL ;
    ANTENNAGATEAREA 0.631200 ;
    ANTENNADIFFAREA 0.434700 ;
    PORT
      LAYER met3 ;
        RECT 0.000 44.240 4.000 44.840 ;
    END
  END p_ll[10]
  PIN p_ll[11]
    DIRECTION INPUT ;
    USE SIGNAL ;
    ANTENNAGATEAREA 0.631200 ;
    ANTENNADIFFAREA 0.434700 ;
    PORT
      LAYER met3 ;
        RECT 0.000 30.640 4.000 31.240 ;
    END
  END p_ll[11]
  PIN p_ll[12]
    DIRECTION INPUT ;
    USE SIGNAL ;
    ANTENNAGATEAREA 0.631200 ;
    ANTENNADIFFAREA 0.434700 ;
    PORT
      LAYER met3 ;
        RECT 0.000 34.040 4.000 34.640 ;
    END
  END p_ll[12]
  PIN p_ll[13]
    DIRECTION INPUT ;
    USE SIGNAL ;
    ANTENNAGATEAREA 0.631200 ;
    ANTENNADIFFAREA 0.434700 ;
    PORT
      LAYER met3 ;
        RECT 46.000 54.440 50.000 55.040 ;
    END
  END p_ll[13]
  PIN p_ll[14]
    DIRECTION INPUT ;
    USE SIGNAL ;
    ANTENNAGATEAREA 0.631200 ;
    ANTENNADIFFAREA 0.434700 ;
    PORT
      LAYER met3 ;
        RECT 0.000 47.640 4.000 48.240 ;
    END
  END p_ll[14]
  PIN p_ll[15]
    DIRECTION INPUT ;
    USE SIGNAL ;
    ANTENNAGATEAREA 0.631200 ;
    ANTENNADIFFAREA 0.434700 ;
    PORT
      LAYER met3 ;
        RECT 0.000 68.040 4.000 68.640 ;
    END
  END p_ll[15]
  PIN p_ll[16]
    DIRECTION INPUT ;
    USE SIGNAL ;
    ANTENNAGATEAREA 0.631200 ;
    ANTENNADIFFAREA 0.434700 ;
    PORT
      LAYER met3 ;
        RECT 0.000 78.240 4.000 78.840 ;
    END
  END p_ll[16]
  PIN p_ll[17]
    DIRECTION INPUT ;
    USE SIGNAL ;
    ANTENNAGATEAREA 0.631200 ;
    ANTENNADIFFAREA 0.434700 ;
    PORT
      LAYER met3 ;
        RECT 0.000 85.040 4.000 85.640 ;
    END
  END p_ll[17]
  PIN p_ll[18]
    DIRECTION INPUT ;
    USE SIGNAL ;
    ANTENNAGATEAREA 0.631200 ;
    ANTENNADIFFAREA 0.434700 ;
    PORT
      LAYER met3 ;
        RECT 0.000 98.640 4.000 99.240 ;
    END
  END p_ll[18]
  PIN p_ll[19]
    DIRECTION INPUT ;
    USE SIGNAL ;
    ANTENNAGATEAREA 0.631200 ;
    ANTENNADIFFAREA 0.434700 ;
    PORT
      LAYER met3 ;
        RECT 0.000 108.840 4.000 109.440 ;
    END
  END p_ll[19]
  PIN p_ll[1]
    DIRECTION INPUT ;
    USE SIGNAL ;
    ANTENNAGATEAREA 0.631200 ;
    ANTENNADIFFAREA 0.434700 ;
    PORT
      LAYER met3 ;
        RECT 0.000 71.440 4.000 72.040 ;
    END
  END p_ll[1]
  PIN p_ll[20]
    DIRECTION INPUT ;
    USE SIGNAL ;
    ANTENNAGATEAREA 0.631200 ;
    ANTENNADIFFAREA 0.434700 ;
    PORT
      LAYER met3 ;
        RECT 0.000 119.040 4.000 119.640 ;
    END
  END p_ll[20]
  PIN p_ll[21]
    DIRECTION INPUT ;
    USE SIGNAL ;
    ANTENNAGATEAREA 0.631200 ;
    ANTENNADIFFAREA 0.434700 ;
    PORT
      LAYER met3 ;
        RECT 0.000 136.040 4.000 136.640 ;
    END
  END p_ll[21]
  PIN p_ll[22]
    DIRECTION INPUT ;
    USE SIGNAL ;
    ANTENNAGATEAREA 0.631200 ;
    ANTENNADIFFAREA 0.434700 ;
    PORT
      LAYER met3 ;
        RECT 0.000 139.440 4.000 140.040 ;
    END
  END p_ll[22]
  PIN p_ll[23]
    DIRECTION INPUT ;
    USE SIGNAL ;
    ANTENNAGATEAREA 0.631200 ;
    ANTENNADIFFAREA 0.434700 ;
    PORT
      LAYER met3 ;
        RECT 0.000 149.640 4.000 150.240 ;
    END
  END p_ll[23]
  PIN p_ll[24]
    DIRECTION INPUT ;
    USE SIGNAL ;
    ANTENNAGATEAREA 0.631200 ;
    ANTENNADIFFAREA 0.434700 ;
    PORT
      LAYER met3 ;
        RECT 0.000 159.840 4.000 160.440 ;
    END
  END p_ll[24]
  PIN p_ll[25]
    DIRECTION INPUT ;
    USE SIGNAL ;
    ANTENNAGATEAREA 0.631200 ;
    ANTENNADIFFAREA 0.434700 ;
    PORT
      LAYER met3 ;
        RECT 0.000 166.640 4.000 167.240 ;
    END
  END p_ll[25]
  PIN p_ll[26]
    DIRECTION INPUT ;
    USE SIGNAL ;
    ANTENNAGATEAREA 0.631200 ;
    ANTENNADIFFAREA 0.434700 ;
    PORT
      LAYER met3 ;
        RECT 0.000 176.840 4.000 177.440 ;
    END
  END p_ll[26]
  PIN p_ll[27]
    DIRECTION INPUT ;
    USE SIGNAL ;
    ANTENNAGATEAREA 0.631200 ;
    ANTENNADIFFAREA 0.434700 ;
    PORT
      LAYER met3 ;
        RECT 0.000 187.040 4.000 187.640 ;
    END
  END p_ll[27]
  PIN p_ll[28]
    DIRECTION INPUT ;
    USE SIGNAL ;
    ANTENNAGATEAREA 0.631200 ;
    ANTENNADIFFAREA 0.434700 ;
    PORT
      LAYER met3 ;
        RECT 0.000 200.640 4.000 201.240 ;
    END
  END p_ll[28]
  PIN p_ll[29]
    DIRECTION INPUT ;
    USE SIGNAL ;
    ANTENNAGATEAREA 0.631200 ;
    ANTENNADIFFAREA 0.434700 ;
    PORT
      LAYER met3 ;
        RECT 0.000 204.040 4.000 204.640 ;
    END
  END p_ll[29]
  PIN p_ll[2]
    DIRECTION INPUT ;
    USE SIGNAL ;
    ANTENNAGATEAREA 0.631200 ;
    ANTENNADIFFAREA 0.434700 ;
    PORT
      LAYER met3 ;
        RECT 46.000 44.240 50.000 44.840 ;
    END
  END p_ll[2]
  PIN p_ll[30]
    DIRECTION INPUT ;
    USE SIGNAL ;
    ANTENNAGATEAREA 0.631200 ;
    ANTENNADIFFAREA 0.434700 ;
    PORT
      LAYER met3 ;
        RECT 0.000 238.040 4.000 238.640 ;
    END
  END p_ll[30]
  PIN p_ll[31]
    DIRECTION INPUT ;
    USE SIGNAL ;
    ANTENNAGATEAREA 0.631200 ;
    ANTENNADIFFAREA 0.434700 ;
    PORT
      LAYER met3 ;
        RECT 0.000 234.640 4.000 235.240 ;
    END
  END p_ll[31]
  PIN p_ll[3]
    DIRECTION INPUT ;
    USE SIGNAL ;
    ANTENNAGATEAREA 0.631200 ;
    ANTENNADIFFAREA 0.434700 ;
    PORT
      LAYER met3 ;
        RECT 0.000 64.640 4.000 65.240 ;
    END
  END p_ll[3]
  PIN p_ll[4]
    DIRECTION INPUT ;
    USE SIGNAL ;
    ANTENNAGATEAREA 0.631200 ;
    ANTENNADIFFAREA 0.434700 ;
    PORT
      LAYER met3 ;
        RECT 0.000 61.240 4.000 61.840 ;
    END
  END p_ll[4]
  PIN p_ll[5]
    DIRECTION INPUT ;
    USE SIGNAL ;
    ANTENNAGATEAREA 0.631200 ;
    ANTENNADIFFAREA 0.434700 ;
    PORT
      LAYER met3 ;
        RECT 0.000 27.240 4.000 27.840 ;
    END
  END p_ll[5]
  PIN p_ll[6]
    DIRECTION INPUT ;
    USE SIGNAL ;
    ANTENNAGATEAREA 0.631200 ;
    ANTENNADIFFAREA 0.434700 ;
    PORT
      LAYER met3 ;
        RECT 0.000 37.440 4.000 38.040 ;
    END
  END p_ll[6]
  PIN p_ll[7]
    DIRECTION INPUT ;
    USE SIGNAL ;
    ANTENNAGATEAREA 0.631200 ;
    ANTENNADIFFAREA 0.434700 ;
    PORT
      LAYER met3 ;
        RECT 0.000 57.840 4.000 58.440 ;
    END
  END p_ll[7]
  PIN p_ll[8]
    DIRECTION INPUT ;
    USE SIGNAL ;
    ANTENNAGATEAREA 0.631200 ;
    ANTENNADIFFAREA 0.434700 ;
    PORT
      LAYER met3 ;
        RECT 46.000 68.040 50.000 68.640 ;
    END
  END p_ll[8]
  PIN p_ll[9]
    DIRECTION INPUT ;
    USE SIGNAL ;
    ANTENNAGATEAREA 0.631200 ;
    ANTENNADIFFAREA 0.434700 ;
    PORT
      LAYER met3 ;
        RECT 46.000 37.440 50.000 38.040 ;
    END
  END p_ll[9]
  PIN rst
    DIRECTION INPUT ;
    USE SIGNAL ;
    ANTENNAGATEAREA 0.631200 ;
    ANTENNADIFFAREA 0.434700 ;
    PORT
      LAYER met3 ;
        RECT 46.000 88.440 50.000 89.040 ;
    END
  END rst
  OBS
      LAYER nwell ;
        RECT 5.330 10.795 44.350 487.070 ;
      LAYER li1 ;
        RECT 5.520 10.795 44.160 486.965 ;
      LAYER met1 ;
        RECT 0.070 5.480 48.690 490.580 ;
      LAYER met2 ;
        RECT 0.650 495.720 3.030 496.810 ;
        RECT 3.870 495.720 6.250 496.810 ;
        RECT 7.090 495.720 9.470 496.810 ;
        RECT 10.310 495.720 12.690 496.810 ;
        RECT 13.530 495.720 15.910 496.810 ;
        RECT 16.750 495.720 19.130 496.810 ;
        RECT 19.970 495.720 22.350 496.810 ;
        RECT 23.190 495.720 25.570 496.810 ;
        RECT 26.410 495.720 28.790 496.810 ;
        RECT 29.630 495.720 32.010 496.810 ;
        RECT 32.850 495.720 35.230 496.810 ;
        RECT 36.070 495.720 38.450 496.810 ;
        RECT 39.290 495.720 41.670 496.810 ;
        RECT 42.510 495.720 44.890 496.810 ;
        RECT 45.730 495.720 48.110 496.810 ;
        RECT 0.100 4.280 48.660 495.720 ;
        RECT 0.650 3.670 3.030 4.280 ;
        RECT 3.870 3.670 6.250 4.280 ;
        RECT 7.090 3.670 9.470 4.280 ;
        RECT 10.310 3.670 12.690 4.280 ;
        RECT 13.530 3.670 15.910 4.280 ;
        RECT 16.750 3.670 19.130 4.280 ;
        RECT 19.970 3.670 22.350 4.280 ;
        RECT 23.190 3.670 25.570 4.280 ;
        RECT 26.410 3.670 28.790 4.280 ;
        RECT 29.630 3.670 32.010 4.280 ;
        RECT 32.850 3.670 35.230 4.280 ;
        RECT 36.070 3.670 38.450 4.280 ;
        RECT 39.290 3.670 41.670 4.280 ;
        RECT 42.510 3.670 44.890 4.280 ;
        RECT 45.730 3.670 48.110 4.280 ;
      LAYER met3 ;
        RECT 0.525 470.240 46.000 487.045 ;
        RECT 4.400 468.840 46.000 470.240 ;
        RECT 0.525 466.840 46.000 468.840 ;
        RECT 4.400 465.440 45.600 466.840 ;
        RECT 0.525 463.440 46.000 465.440 ;
        RECT 4.400 462.040 45.600 463.440 ;
        RECT 0.525 460.040 46.000 462.040 ;
        RECT 4.400 458.640 46.000 460.040 ;
        RECT 0.525 456.640 46.000 458.640 ;
        RECT 4.400 455.240 46.000 456.640 ;
        RECT 0.525 453.240 46.000 455.240 ;
        RECT 4.400 451.840 46.000 453.240 ;
        RECT 0.525 449.840 46.000 451.840 ;
        RECT 4.400 448.440 46.000 449.840 ;
        RECT 0.525 446.440 46.000 448.440 ;
        RECT 4.400 445.040 46.000 446.440 ;
        RECT 0.525 443.040 46.000 445.040 ;
        RECT 4.400 441.640 46.000 443.040 ;
        RECT 0.525 436.240 46.000 441.640 ;
        RECT 4.400 434.840 46.000 436.240 ;
        RECT 0.525 432.840 46.000 434.840 ;
        RECT 4.400 431.440 46.000 432.840 ;
        RECT 0.525 429.440 46.000 431.440 ;
        RECT 4.400 428.040 46.000 429.440 ;
        RECT 0.525 422.640 46.000 428.040 ;
        RECT 4.400 421.240 46.000 422.640 ;
        RECT 0.525 419.240 46.000 421.240 ;
        RECT 4.400 417.840 46.000 419.240 ;
        RECT 0.525 415.840 46.000 417.840 ;
        RECT 4.400 414.440 46.000 415.840 ;
        RECT 0.525 412.440 46.000 414.440 ;
        RECT 4.400 411.040 46.000 412.440 ;
        RECT 0.525 405.640 46.000 411.040 ;
        RECT 4.400 404.240 46.000 405.640 ;
        RECT 0.525 402.240 46.000 404.240 ;
        RECT 4.400 400.840 46.000 402.240 ;
        RECT 0.525 398.840 46.000 400.840 ;
        RECT 4.400 397.440 46.000 398.840 ;
        RECT 0.525 395.440 46.000 397.440 ;
        RECT 4.400 394.040 46.000 395.440 ;
        RECT 0.525 392.040 46.000 394.040 ;
        RECT 4.400 390.640 46.000 392.040 ;
        RECT 0.525 388.640 46.000 390.640 ;
        RECT 4.400 387.240 46.000 388.640 ;
        RECT 0.525 385.240 46.000 387.240 ;
        RECT 4.400 383.840 46.000 385.240 ;
        RECT 0.525 381.840 46.000 383.840 ;
        RECT 4.400 380.440 46.000 381.840 ;
        RECT 0.525 378.440 46.000 380.440 ;
        RECT 4.400 377.040 46.000 378.440 ;
        RECT 0.525 375.040 46.000 377.040 ;
        RECT 4.400 373.640 45.600 375.040 ;
        RECT 0.525 371.640 46.000 373.640 ;
        RECT 4.400 370.240 46.000 371.640 ;
        RECT 0.525 368.240 46.000 370.240 ;
        RECT 4.400 366.840 46.000 368.240 ;
        RECT 0.525 364.840 46.000 366.840 ;
        RECT 4.400 363.440 45.600 364.840 ;
        RECT 0.525 361.440 46.000 363.440 ;
        RECT 4.400 360.040 46.000 361.440 ;
        RECT 0.525 358.040 46.000 360.040 ;
        RECT 4.400 356.640 46.000 358.040 ;
        RECT 0.525 354.640 46.000 356.640 ;
        RECT 4.400 353.240 45.600 354.640 ;
        RECT 0.525 351.240 46.000 353.240 ;
        RECT 4.400 349.840 46.000 351.240 ;
        RECT 0.525 347.840 46.000 349.840 ;
        RECT 4.400 346.440 45.600 347.840 ;
        RECT 0.525 344.440 46.000 346.440 ;
        RECT 4.400 343.040 46.000 344.440 ;
        RECT 0.525 341.040 46.000 343.040 ;
        RECT 4.400 339.640 46.000 341.040 ;
        RECT 0.525 337.640 46.000 339.640 ;
        RECT 4.400 336.240 45.600 337.640 ;
        RECT 0.525 334.240 46.000 336.240 ;
        RECT 4.400 332.840 46.000 334.240 ;
        RECT 0.525 330.840 46.000 332.840 ;
        RECT 4.400 329.440 45.600 330.840 ;
        RECT 0.525 327.440 46.000 329.440 ;
        RECT 4.400 326.040 46.000 327.440 ;
        RECT 0.525 324.040 46.000 326.040 ;
        RECT 4.400 322.640 46.000 324.040 ;
        RECT 0.525 320.640 46.000 322.640 ;
        RECT 4.400 319.240 46.000 320.640 ;
        RECT 0.525 317.240 46.000 319.240 ;
        RECT 4.400 315.840 45.600 317.240 ;
        RECT 0.525 313.840 46.000 315.840 ;
        RECT 4.400 312.440 46.000 313.840 ;
        RECT 0.525 310.440 46.000 312.440 ;
        RECT 4.400 309.040 46.000 310.440 ;
        RECT 0.525 307.040 46.000 309.040 ;
        RECT 4.400 305.640 46.000 307.040 ;
        RECT 0.525 303.640 46.000 305.640 ;
        RECT 4.400 302.240 45.600 303.640 ;
        RECT 0.525 300.240 46.000 302.240 ;
        RECT 4.400 298.840 46.000 300.240 ;
        RECT 0.525 296.840 46.000 298.840 ;
        RECT 4.400 295.440 46.000 296.840 ;
        RECT 0.525 293.440 46.000 295.440 ;
        RECT 4.400 292.040 46.000 293.440 ;
        RECT 0.525 290.040 46.000 292.040 ;
        RECT 4.400 288.640 46.000 290.040 ;
        RECT 0.525 286.640 46.000 288.640 ;
        RECT 4.400 285.240 45.600 286.640 ;
        RECT 0.525 283.240 46.000 285.240 ;
        RECT 4.400 281.840 45.600 283.240 ;
        RECT 0.525 279.840 46.000 281.840 ;
        RECT 4.400 278.440 46.000 279.840 ;
        RECT 0.525 276.440 46.000 278.440 ;
        RECT 4.400 275.040 45.600 276.440 ;
        RECT 0.525 273.040 46.000 275.040 ;
        RECT 4.400 271.640 46.000 273.040 ;
        RECT 0.525 269.640 46.000 271.640 ;
        RECT 4.400 268.240 46.000 269.640 ;
        RECT 0.525 266.240 46.000 268.240 ;
        RECT 4.400 264.840 45.600 266.240 ;
        RECT 0.525 262.840 46.000 264.840 ;
        RECT 4.400 261.440 46.000 262.840 ;
        RECT 0.525 259.440 46.000 261.440 ;
        RECT 4.400 258.040 46.000 259.440 ;
        RECT 0.525 256.040 46.000 258.040 ;
        RECT 4.400 254.640 45.600 256.040 ;
        RECT 0.525 252.640 46.000 254.640 ;
        RECT 4.400 251.240 46.000 252.640 ;
        RECT 0.525 249.240 46.000 251.240 ;
        RECT 4.400 247.840 46.000 249.240 ;
        RECT 0.525 245.840 46.000 247.840 ;
        RECT 4.400 244.440 46.000 245.840 ;
        RECT 0.525 242.440 46.000 244.440 ;
        RECT 4.400 241.040 45.600 242.440 ;
        RECT 0.525 239.040 46.000 241.040 ;
        RECT 4.400 237.640 46.000 239.040 ;
        RECT 0.525 235.640 46.000 237.640 ;
        RECT 4.400 234.240 45.600 235.640 ;
        RECT 0.525 232.240 46.000 234.240 ;
        RECT 4.400 230.840 46.000 232.240 ;
        RECT 0.525 228.840 46.000 230.840 ;
        RECT 4.400 227.440 46.000 228.840 ;
        RECT 0.525 225.440 46.000 227.440 ;
        RECT 4.400 224.040 45.600 225.440 ;
        RECT 0.525 222.040 46.000 224.040 ;
        RECT 4.400 220.640 46.000 222.040 ;
        RECT 0.525 218.640 46.000 220.640 ;
        RECT 4.400 217.240 46.000 218.640 ;
        RECT 0.525 215.240 46.000 217.240 ;
        RECT 4.400 213.840 46.000 215.240 ;
        RECT 0.525 211.840 46.000 213.840 ;
        RECT 4.400 210.440 45.600 211.840 ;
        RECT 0.525 208.440 46.000 210.440 ;
        RECT 4.400 207.040 45.600 208.440 ;
        RECT 0.525 205.040 46.000 207.040 ;
        RECT 4.400 203.640 46.000 205.040 ;
        RECT 0.525 201.640 46.000 203.640 ;
        RECT 4.400 200.240 46.000 201.640 ;
        RECT 0.525 198.240 46.000 200.240 ;
        RECT 4.400 196.840 45.600 198.240 ;
        RECT 0.525 194.840 46.000 196.840 ;
        RECT 4.400 193.440 46.000 194.840 ;
        RECT 0.525 191.440 46.000 193.440 ;
        RECT 4.400 190.040 46.000 191.440 ;
        RECT 0.525 188.040 46.000 190.040 ;
        RECT 4.400 186.640 46.000 188.040 ;
        RECT 0.525 184.640 46.000 186.640 ;
        RECT 4.400 183.240 45.600 184.640 ;
        RECT 0.525 181.240 46.000 183.240 ;
        RECT 4.400 179.840 46.000 181.240 ;
        RECT 0.525 177.840 46.000 179.840 ;
        RECT 4.400 176.440 46.000 177.840 ;
        RECT 0.525 174.440 46.000 176.440 ;
        RECT 4.400 173.040 46.000 174.440 ;
        RECT 0.525 171.040 46.000 173.040 ;
        RECT 4.400 169.640 45.600 171.040 ;
        RECT 0.525 167.640 46.000 169.640 ;
        RECT 4.400 166.240 46.000 167.640 ;
        RECT 0.525 164.240 46.000 166.240 ;
        RECT 4.400 162.840 46.000 164.240 ;
        RECT 0.525 160.840 46.000 162.840 ;
        RECT 4.400 159.440 45.600 160.840 ;
        RECT 0.525 157.440 46.000 159.440 ;
        RECT 4.400 156.040 46.000 157.440 ;
        RECT 0.525 154.040 46.000 156.040 ;
        RECT 4.400 152.640 45.600 154.040 ;
        RECT 0.525 150.640 46.000 152.640 ;
        RECT 4.400 149.240 46.000 150.640 ;
        RECT 0.525 147.240 46.000 149.240 ;
        RECT 4.400 145.840 46.000 147.240 ;
        RECT 0.525 143.840 46.000 145.840 ;
        RECT 4.400 142.440 46.000 143.840 ;
        RECT 0.525 140.440 46.000 142.440 ;
        RECT 4.400 139.040 45.600 140.440 ;
        RECT 0.525 137.040 46.000 139.040 ;
        RECT 4.400 135.640 46.000 137.040 ;
        RECT 0.525 133.640 46.000 135.640 ;
        RECT 4.400 132.240 46.000 133.640 ;
        RECT 0.525 130.240 46.000 132.240 ;
        RECT 4.400 128.840 46.000 130.240 ;
        RECT 0.525 126.840 46.000 128.840 ;
        RECT 4.400 125.440 45.600 126.840 ;
        RECT 0.525 123.440 46.000 125.440 ;
        RECT 4.400 122.040 46.000 123.440 ;
        RECT 0.525 120.040 46.000 122.040 ;
        RECT 4.400 118.640 45.600 120.040 ;
        RECT 0.525 116.640 46.000 118.640 ;
        RECT 4.400 115.240 46.000 116.640 ;
        RECT 0.525 113.240 46.000 115.240 ;
        RECT 4.400 111.840 46.000 113.240 ;
        RECT 0.525 109.840 46.000 111.840 ;
        RECT 4.400 108.440 46.000 109.840 ;
        RECT 0.525 106.440 46.000 108.440 ;
        RECT 4.400 105.040 46.000 106.440 ;
        RECT 0.525 103.040 46.000 105.040 ;
        RECT 4.400 101.640 46.000 103.040 ;
        RECT 0.525 99.640 46.000 101.640 ;
        RECT 4.400 98.240 46.000 99.640 ;
        RECT 0.525 96.240 46.000 98.240 ;
        RECT 4.400 94.840 46.000 96.240 ;
        RECT 0.525 92.840 46.000 94.840 ;
        RECT 4.400 91.440 46.000 92.840 ;
        RECT 0.525 89.440 46.000 91.440 ;
        RECT 4.400 88.040 45.600 89.440 ;
        RECT 0.525 86.040 46.000 88.040 ;
        RECT 4.400 84.640 46.000 86.040 ;
        RECT 0.525 82.640 46.000 84.640 ;
        RECT 4.400 81.240 46.000 82.640 ;
        RECT 0.525 79.240 46.000 81.240 ;
        RECT 4.400 77.840 46.000 79.240 ;
        RECT 0.525 75.840 46.000 77.840 ;
        RECT 4.400 74.440 46.000 75.840 ;
        RECT 0.525 72.440 46.000 74.440 ;
        RECT 4.400 71.040 46.000 72.440 ;
        RECT 0.525 69.040 46.000 71.040 ;
        RECT 4.400 67.640 45.600 69.040 ;
        RECT 0.525 65.640 46.000 67.640 ;
        RECT 4.400 64.240 45.600 65.640 ;
        RECT 0.525 62.240 46.000 64.240 ;
        RECT 4.400 60.840 46.000 62.240 ;
        RECT 0.525 58.840 46.000 60.840 ;
        RECT 4.400 57.440 45.600 58.840 ;
        RECT 0.525 55.440 46.000 57.440 ;
        RECT 0.525 54.040 45.600 55.440 ;
        RECT 0.525 48.640 46.000 54.040 ;
        RECT 4.400 47.240 46.000 48.640 ;
        RECT 0.525 45.240 46.000 47.240 ;
        RECT 4.400 43.840 45.600 45.240 ;
        RECT 0.525 41.840 46.000 43.840 ;
        RECT 0.525 40.440 45.600 41.840 ;
        RECT 0.525 38.440 46.000 40.440 ;
        RECT 4.400 37.040 45.600 38.440 ;
        RECT 0.525 35.040 46.000 37.040 ;
        RECT 4.400 33.640 45.600 35.040 ;
        RECT 0.525 31.640 46.000 33.640 ;
        RECT 4.400 30.240 46.000 31.640 ;
        RECT 0.525 28.240 46.000 30.240 ;
        RECT 4.400 26.840 46.000 28.240 ;
        RECT 0.525 10.715 46.000 26.840 ;
      LAYER met4 ;
        RECT 3.975 87.895 20.640 476.505 ;
        RECT 23.040 87.895 23.940 476.505 ;
        RECT 26.340 87.895 41.105 476.505 ;
  END
END stage3
END LIBRARY

